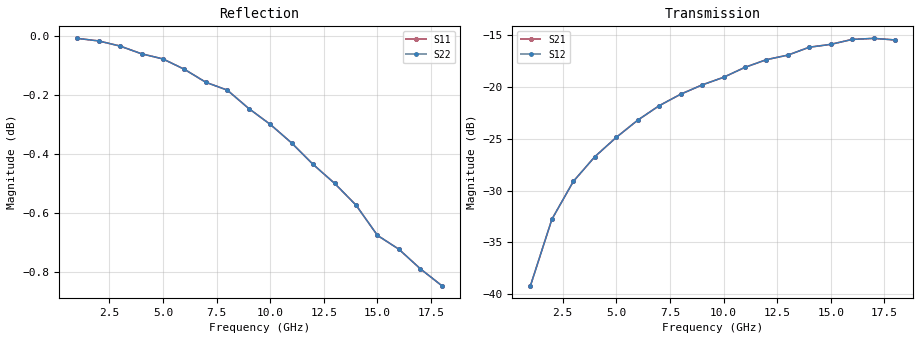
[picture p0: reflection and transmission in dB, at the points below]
!HPND-4018 beam lead PIN diode
!Series configuration S-parameters Vr=10 V.  Last updated 10/3/97
# mhz s ma r 50
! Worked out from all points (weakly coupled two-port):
!   18 points, 1 GHz to 18 GHz, reference 50 ohm
!   highest |S21| = -15.34 dB at 17 GHz (marker M1); lowest = -39.2 dB at 1 GHz (marker M2)
!   lowest |S11| = -0.8 dB at 18 GHz (marker M3), VSWR 20.51, Z = 25 - j150 ohm
!   |S11| at or under -10 dB: nowhere
!   |S22| runs from -0.8 to 0.0 dB; largest |S21 - S12| = 0
!   S11 on the Smith chart (normalised r, x): 1 GHz: 2, -57; 5 GHz: 1, -11; 11 GHz: 0.52, -4.86; 18 GHz: 0.50, -3.00
1000  0.999 -2.0  0.011 93.0  0.011 93.0  0.999 -2.0
2000  0.998 -4.0  0.023 85.0  0.023 85.0  0.998 -4.0
3000  0.996 -6.0  0.035 83.0  0.035 83.0  0.996 -6.0
4000  0.993 -8.0  0.046 81.0  0.046 81.0  0.993 -8.0
5000  0.991 -10.0  0.057 78.0  0.057 78.0  0.991 -10.0
6000  0.987 -12.0  0.069 76.0  0.069 76.0  0.987 -12.0
7000  0.982 -14.0  0.081 73.0  0.081 73.0  0.982 -14.0
8000  0.979 -16.0  0.092 71.0  0.092 71.0  0.979 -16.0
9000  0.972 -18.0  0.102 68.0  0.102 68.0  0.972 -18.0
10000  0.966 -20.0  0.111 67.0  0.111 67.0  0.966 -20.0
11000  0.959 -23.0  0.124 63.0  0.124 63.0  0.959 -23.0
12000  0.951 -25.0  0.135 62.0  0.135 62.0  0.951 -25.0
13000  0.944 -27.0  0.142 59.0  0.142 59.0  0.944 -27.0
14000  0.936 -29.0  0.155 55.0  0.155 55.0  0.936 -29.0
15000  0.925 -31.0  0.16 53.0  0.16 53.0  0.925 -31.0
16000  0.92 -33.0  0.169 48.0  0.169 48.0  0.92 -33.0
17000  0.913 -34.0  0.171 45.0  0.171 45.0  0.913 -34.0
18000  0.907 -36.0  0.168 41.0  0.168 41.0  0.907 -36.0
